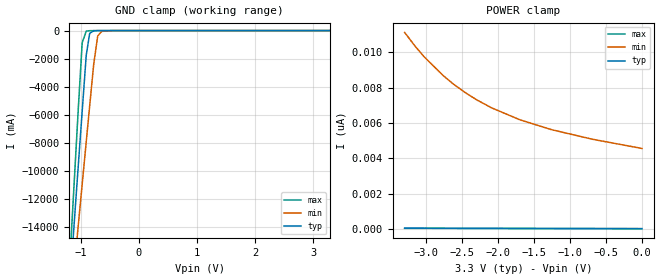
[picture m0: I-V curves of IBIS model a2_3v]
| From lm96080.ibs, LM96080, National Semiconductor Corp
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[Model] a2_3v
Model_type Input
Vinh = 2.0V
Vinl = 0.8V
C_comp   1.18pF   1.09pF   1.35pF
[Voltage Range]   3.3V   3.0V   3.6V
[Temperature Range]   25.0   125.0   -40.0
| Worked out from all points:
|   GND clamp passes 1 mA (typ) near -0.65 V on its own axis
[GND Clamp]
-3.3V     -140.9A    -112.5A    -173A
-1.171V   -17.28A    -19.67A    -15.31A
-1.102V   -13.23A    -16.62A    -10.16A
-1.043V   -9.774A    -14.01A    -5.763A
-973.5mV  -5.764A    -10.98A    -872.2mA
-904.2mV  -1.783A    -7.965A    -42.01mA
-844.8mV  -197.3mA   -5.398A    -8.068mA
-775.5mV  -19.36mA   -2.42A     -2.167mA
-706.2mV  -3.206mA   -385.4mA   -450.9uA
-636.9mV  -646.1uA   -55.93mA   -65.71uA
-438.9mV  -3.11uA    -355uA     -57.03nA
3.293V    21.88pA    0A         19.76pA
[POWER Clamp]
-3.3V     49.64pA    11.13nA    41.58pA
-3.161V   47.87pA    10.38nA    40.75pA
-3.033V   46.33pA    9.768nA    39.98pA
-2.765V   43.37pA    8.687nA    38.37pA
-2.627V   41.96pA    8.219nA    37.54pA
-2.458V   40.33pA    7.722nA    36.53pA
-2.3V     38.88pA    7.316nA    35.58pA
-2.092V   37.07pA    6.86nA     34.33pA
-1.696V   33.87pA    6.18nA     31.96pA
-1.261V   30.62pA    5.627nA    29.34pA
-696.3mV  26.64pA    5.087nA    25.96pA
-3.3mV    21.95pA    4.562nA    21.8pA
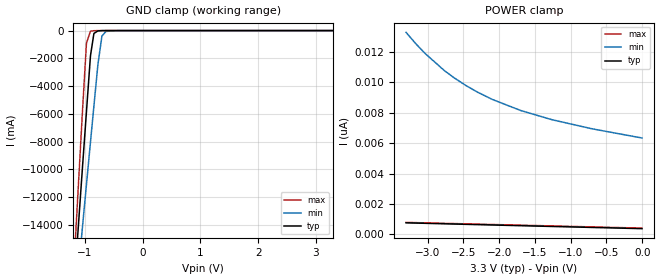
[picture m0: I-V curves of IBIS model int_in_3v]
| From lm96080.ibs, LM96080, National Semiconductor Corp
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[Model] int_in_3v
Model_type Input
Vinh = 2.0V
Vinl = 0.8V
C_comp   1.15pF   1.07pF   1.33pF
[Voltage Range]   3.3V   3.0V   3.6V
[Temperature Range]   25.0   125.0   -40.0
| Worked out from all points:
|   GND clamp passes 1 mA (typ) near -0.64 V on its own axis
[GND Clamp]
-3.3V     -142.3A    -113.8A    -174.6A
-1.171V   -17.47A    -19.9A     -15.46A
-1.102V   -13.36A    -16.8A     -10.25A
-1.043V   -9.856A    -14.14A    -5.81A
-973.5mV  -5.807A    -11.07A    -890.6mA
-904.2mV  -1.803A    -8.02A     -47.69mA
-844.8mV  -206.9mA   -5.432A    -9.694mA
-775.5mV  -22.71mA   -2.439A    -2.496mA
-706.2mV  -4.017mA   -395.4mA   -504uA
-636.9mV  -790.8uA   -60.84mA   -72.22uA
-438.9mV  -3.429uA   -514.1uA   -60.75nA
3.293V    377.6pA    0A         375.5pA
[POWER Clamp]
-3.3V     762.5pA    13.28nA    790pA
-3.161V   745.7pA    12.52nA    774.2pA
-3.033V   730.3pA    11.89nA    759.6pA
-2.765V   698.5pA    10.77nA    729.1pA
-2.627V   682.1pA    10.29nA    713.3pA
-2.458V   662.3pA    9.772nA    694.1pA
-2.3V     643.7pA    9.348nA    676pA
-2.092V   619.5pA    8.868nA    652.3pA
-1.696V   573.5pA    8.143nA    607.2pA
-1.261V   523.2pA    7.541nA    557.5pA
-696.3mV  458.3pA    6.939nA    493.2pA
-3.3mV    378.7pA    6.339nA    414.2pA
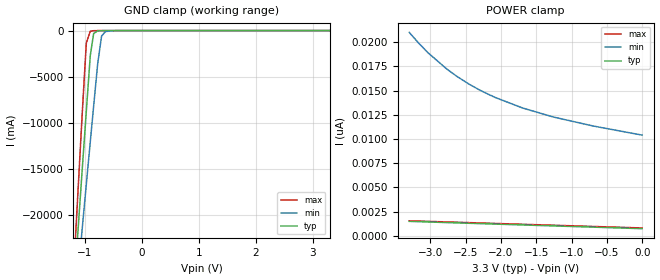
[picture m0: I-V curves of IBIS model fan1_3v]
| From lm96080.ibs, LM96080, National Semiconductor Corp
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[Model] fan1_3v
Model_type Input
Vinh = 2.1V
Vinl = 0.99V
C_comp   3.02pF   2.81pF   3.44pF
[Voltage Range]   3.3V   3.0V   3.6V
[Temperature Range]   25.0   125.0   -40.0
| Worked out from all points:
|   GND clamp passes 1 mA (typ) near -0.62 V on its own axis
[GND Clamp]
-3.3V     -214.3A    -171.4A    -262.7A
-1.171V   -26.3A     -29.96A    -23.27A
-1.102V   -20.1A     -25.28A    -15.41A
-1.043V   -14.82A    -21.28A    -8.74A
-973.5mV  -8.732A    -16.64A    -1.345A
-904.2mV  -2.715A    -12.06A    -74.37mA
-844.8mV  -315.1mA   -8.165A    -15.35mA
-775.5mV  -35.73mA   -3.667A    -3.909mA
-706.2mV  -6.43mA    -598.1mA   -782.7uA
-636.9mV  -1.259mA   -93.72mA   -111.6uA
-438.9mV  -5.304uA   -850.7uA   -92.98nA
3.293V    744.2pA    0A         741pA
[POWER Clamp]
-3.3V     1.5nA      21nA       1.559nA
-3.161V   1.468nA    19.85nA    1.528nA
-3.033V   1.437nA    18.89nA    1.499nA
-2.765V   1.375nA    17.2nA     1.439nA
-2.627V   1.343nA    16.47nA    1.408nA
-2.458V   1.304nA    15.68nA    1.37nA
-2.3V     1.268nA    15.04nA    1.334nA
-2.092V   1.22nA     14.31nA    1.287nA
-1.696V   1.13nA     13.2nA     1.198nA
-1.261V   1.031nA    12.27nA    1.1nA
-696.3mV  903.2pA    11.34nA    973.4pA
-3.3mV    746.5pA    10.4nA     817.5pA
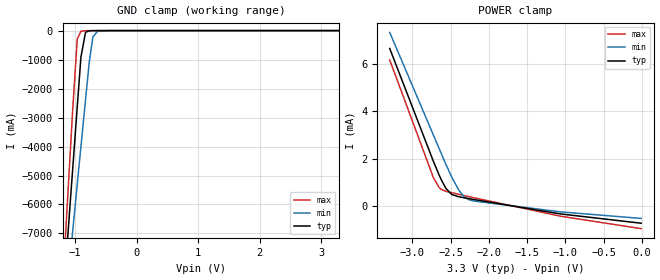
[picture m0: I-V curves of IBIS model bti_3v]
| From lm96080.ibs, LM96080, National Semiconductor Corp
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[Model] bti_3v
Model_type Input
Vinh = 2.0V
Vinl = 0.8V
C_comp   2.30pF   2.10pF   2.51pF
[Voltage Range]   3.3V   3.0V   3.6V
[Temperature Range]   25.0   125.0   -40.0
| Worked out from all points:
|   POWER clamp passes 1 mA (typ) near -2.60 V on its own axis
[GND Clamp]
-3.29V    -70.15A    -56.02A    -86.12A
-1.175V   -8.746A    -9.914A    -7.788A
-1.1V     -6.553A    -8.263A    -4.998A
-1.04V    -4.807A    -6.945A    -2.78A
-965mV    -2.638A    -5.305A    -292.7mA
-905mV    -915.6mA   -4.001A    -23.11mA
-830mV    -59.08mA   -2.381A    -4.486mA
-770mV    -9.278mA   -1.093A    -2.438mA
-710mV    -2.795mA   -215.3mA   -1.715mA
-635mV    -1.35mA    -27.25mA   -1.496mA
-440mV    -1.04mA    -881.8uA   -1.461mA
3.295V    -716.6uA   0A         -1.12mA
[POWER Clamp]
-3.295V   6.637mA    7.314mA    6.158mA
-2.725V   1.896mA    3mA        1.209mA
-2.65V    1.318mA    2.433mA    792.4uA
-2.62V    1.107mA    2.206mA    707.9uA
-2.56V    750.1uA    1.756mA    630.8uA
-2.485V   497uA      1.229mA    572.6uA
-2.395V   402.9uA    691.8uA    506.4uA
-2.32V    356.5uA    393.2uA    451.3uA
-2.26V    321.1uA    275.8uA    407.2uA
-2.2V     285.9uA    222.1uA    363.1uA
-1.06V    -322.7uA   -235.4uA   -418.8uA
-10mV     -712.3uA   -510.2uA   -940.6uA
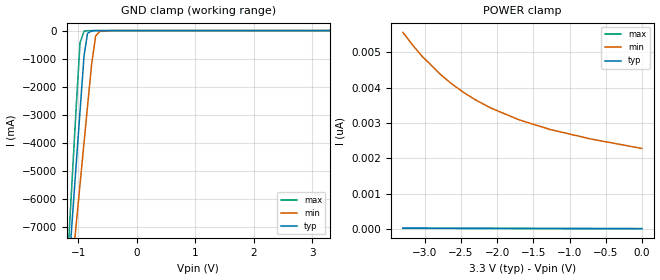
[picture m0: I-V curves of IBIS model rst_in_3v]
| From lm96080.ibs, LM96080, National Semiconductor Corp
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[Model] rst_in_3v
Model_type Input
Vinh = 2.0V
Vinl = 0.8V
C_comp   0.66pF   0.63pF   0.74pF
[Voltage Range]   3.3V   3.0V   3.6V
[Temperature Range]   25.0   125.0   -40.0
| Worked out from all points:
|   GND clamp passes 1 mA (typ) near -0.67 V on its own axis
[GND Clamp]
-3.3V     -70.44A    -56.24A    -86.49A
-1.171V   -8.642A    -9.836A    -7.656A
-1.102V   -6.616A    -8.311A    -5.079A
-1.043V   -4.887A    -7.006A    -2.881A
-973.5mV  -2.882A    -5.489A    -436.1mA
-904.2mV  -891.7mA   -3.983A    -21.01mA
-844.8mV  -98.65mA   -2.699A    -4.034mA
-775.5mV  -9.682mA   -1.21A     -1.083mA
-706.2mV  -1.603mA   -192.7mA   -225.4uA
-636.9mV  -323.1uA   -27.96mA   -32.85uA
-438.9mV  -1.555uA   -177.5uA   -28.52nA
3.293V    10.94pA    0A         9.88pA
[POWER Clamp]
-3.3V     24.82pA    5.565nA    20.79pA
-3.161V   23.94pA    5.192nA    20.38pA
-3.033V   23.16pA    4.884nA    19.99pA
-2.765V   21.69pA    4.344nA    19.19pA
-2.627V   20.98pA    4.11nA     18.77pA
-2.458V   20.17pA    3.861nA    18.27pA
-2.3V     19.44pA    3.658nA    17.79pA
-2.092V   18.54pA    3.43nA     17.17pA
-1.696V   16.94pA    3.09nA     15.98pA
-1.261V   15.31pA    2.813nA    14.67pA
-696.3mV  13.32pA    2.544nA    12.98pA
-3.3mV    10.97pA    2.281nA    10.9pA
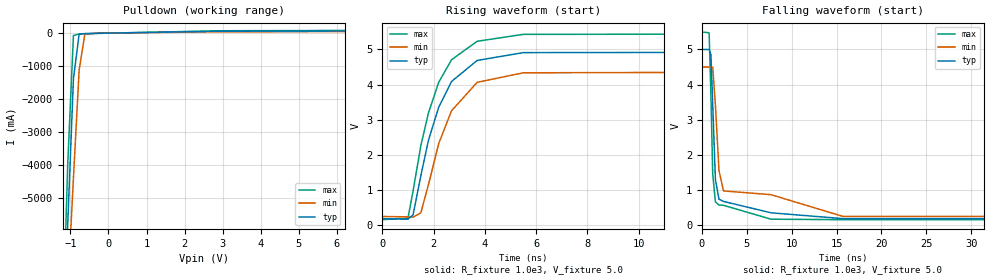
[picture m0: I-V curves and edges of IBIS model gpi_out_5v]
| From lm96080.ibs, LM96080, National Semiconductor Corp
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[Model] gpi_out_5v
Model_type Open_sink
Vmeas = 0.4V
Cref = 0.0pF
Rref = 1.0e3
Vref = 5.0V
C_comp   1.16pF   1.07pF   1.33pF
[Voltage Range]   5.0V   4.5V   5.5V
[Temperature Range]   25.0   125.0   -40.0
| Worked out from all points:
|   slope of the pulldown table from 0 to 0.75 V, typ, clamps not added: 38.1 ohm
|   rising waveform, R_fixture 1.0e3, V_fixture 5.0: 20-80 % time 1.22ns typ, 1.25ns min, 1.19ns max; typ from 0.17 V to 5 V
|   falling waveform, R_fixture 1.0e3, V_fixture 5.0: 20-80 % time 425ps typ, 736ps min, 312ps max; typ from 5 V to 0.17 V
[Pulldown]
-5V       -121.7A    -95.03A    -151.5A
-1.22V    -10.3A     -11.17A    -9.688A
-1.07V    -5.792A    -7.757A    -3.976A
-920mV    -1.386A    -4.392A    -75.54mA
-770mV    -30.71mA   -1.118A    -28.64mA
-620mV    -17.35mA   -31.1mA    -22.65mA
-305mV    -8.646mA   -5.705mA   -11.55mA
2.875V    53.3mA     36.61mA    67.81mA
10V       68.75mA    48.56mA    87.6mA
[Rising Waveform]
R_fixture=1.0e3
V_fixture=5.0
V_fixture_min=4.5
V_fixture_max=5.5
0s        170.3mV    231.6mV    140.1mV
1ns       153.4mV    220.5mV    188.2mV
1.2ns     279.8mV    212.2mV    962mV
1.5ns     1.39V      334mV      2.248V
1.8ns     2.41V      1.144V     3.19V
2.2ns     3.352V     2.314V     4.064V
2.7ns     4.086V     3.25V      4.707V
3.7ns     4.687V     4.062V     5.234V
5.5ns     4.91V      4.334V     5.432V
99.95ns   5V         4.5V       5.5V
[Falling Waveform]
R_fixture=1.0e3
V_fixture=5.0
V_fixture_min=4.5
V_fixture_max=5.5
0s        5V         4.5V       5.5V
800ps     5V         4.5V       5.475V
1ns       4.857V     4.5V       3.713V
1.2ns     3.431V     4.494V     1.451V
1.5ns     1.286V     3.414V     649.8mV
1.9ns     723.9mV    1.541V     557.7mV
2.4ns     661.6mV    961.3mV    551mV
7.7ns     336.5mV    854mV      153.9mV
15.7ns    170.4mV    234.2mV    140.2mV
99.95ns   170.3mV    231.6mV    140.1mV
[Ramp]
R_load = 1.0e3
dV/dt_r   2.897827E0/1.2E-9   2.561003E0/1.3E-9   3.215929E0/1.2E-9
dV/dt_f   2.89783E0/4E-10   2.561008E0/7E-10   3.215933E0/3E-10
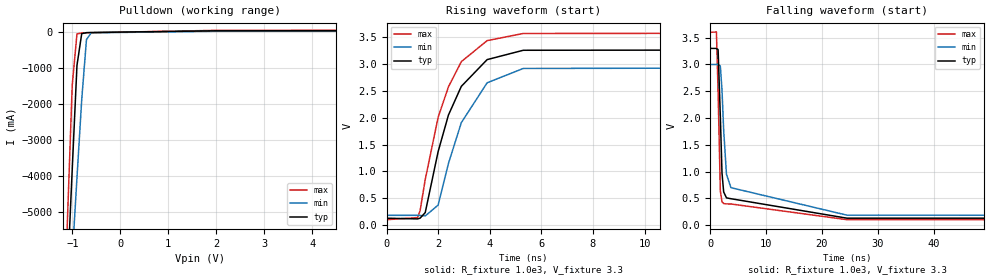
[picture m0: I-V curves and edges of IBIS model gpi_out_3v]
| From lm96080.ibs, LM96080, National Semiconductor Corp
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[Model] gpi_out_3v
Model_type Open_sink
Vmeas = 0.4V
Cref = 0.0pF
Rref = 1.0e3
Vref = 5.0V
C_comp   1.16pF   1.07pF   1.33pF
[Voltage Range]   3.3V   3.0V   3.6V
[Temperature Range]   25.0   125.0   -40.0
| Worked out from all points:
|   slope of the pulldown table from 0 to 0.495 V, typ, clamps not added: 43.7 ohm
|   rising waveform, R_fixture 1.0e3, V_fixture 3.3: 20-80 % time 1.26ns typ, 1.3ns min, 1.22ns max; typ from 0.129 V to 3.3 V
|   falling waveform, R_fixture 1.0e3, V_fixture 3.3: 20-80 % time 585ps typ, 1.22ns min, 393ps max; typ from 3.3 V to 0.129 V
[Pulldown]
-3.3V     -71.91A    -57.56A    -88.1A
-1.201V   -9.732A    -10.74A    -8.963A
-1.102V   -6.751A    -8.487A    -5.188A
-1.003V   -3.809A    -6.247A    -1.477A
-904.2mV  -926.6mA   -4.041A    -53.12mA
-805.2mV  -46.96mA   -1.877A    -28.28mA
-706.2mV  -19.05mA   -209.7mA   -23.38mA
-607.2mV  -14.94mA   -23.83mA   -20.14mA
1.996V    31.68mA    20.03mA    44.46mA
6.6V      35.4mA     22.46mA    49.81mA
[Rising Waveform]
R_fixture=1.0e3
V_fixture=3.3
V_fixture_min=3.0
V_fixture_max=3.6
0s        129.5mV    183.6mV    101.8mV
1.2ns     116.6mV    182.2mV    139.7mV
1.3ns     129.8mV    180.2mV    265.7mV
1.5ns     233.3mV    171.5mV    850mV
2ns       1.37V      373.9mV    2.009V
2.4ns     2.052V     1.15V      2.578V
2.9ns     2.587V     1.911V     3.047V
3.9ns     3.085V     2.653V     3.439V
5.3ns     3.259V     2.92V      3.572V
99.95ns   3.3V       3V         3.6V
[Falling Waveform]
R_fixture=1.0e3
V_fixture=3.3
V_fixture_min=3.0
V_fixture_max=3.6
0s        3.3V       3V         3.6V
1.1ns     3.3V       3V         3.607V
1.4ns     3.278V     3V         2.489V
1.8ns     2.034V     2.972V     638.8mV
2.1ns     975.9mV    2.523V     434.4mV
2.4ns     619mV      1.775V     403.9mV
2.9ns     509.5mV    951.5mV    396.3mV
3.7ns     493.4mV    699.6mV    395.1mV
24.5ns    129.6mV    186.1mV    101.8mV
99.95ns   129.5mV    183.6mV    101.8mV
[Ramp]
R_load = 1.0e3
dV/dt_r   1.902308E0/1.2E-9   1.689858E0/1.3E-9   2.098945E0/1.3E-9
dV/dt_f   1.90231E0/6E-10   1.689861E0/1.2E-9   2.098945E0/4E-10
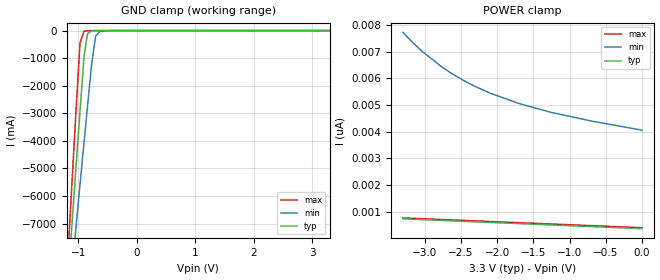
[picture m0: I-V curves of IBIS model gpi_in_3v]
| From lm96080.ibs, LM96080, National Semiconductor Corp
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[Model] gpi_in_3v
Model_type Input
Vinh = 2.0V
Vinl = 0.8V
C_comp   1.16pF   1.07pF   1.33pF
[Voltage Range]   3.3V   3.0V   3.6V
[Temperature Range]   25.0   125.0   -40.0
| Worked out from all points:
|   GND clamp passes 1 mA (typ) near -0.66 V on its own axis
[GND Clamp]
-3.3V     -71.91A    -57.56A    -88.1A
-1.171V   -8.827A    -10.06A    -7.809A
-1.102V   -6.741A    -8.485A    -5.168A
-1.043V   -4.968A    -7.137A    -2.929A
-973.5mV  -2.925A    -5.578A    -454.5mA
-904.2mV  -911.7mA   -4.037A    -26.68mA
-844.8mV  -108.2mA   -2.733A    -5.66mA
-775.5mV  -13.03mA   -1.229A    -1.413mA
-706.2mV  -2.413mA   -202.7mA   -278.6uA
-636.9mV  -467.8uA   -32.88mA   -39.36uA
-438.9mV  -1.874uA   -336.6uA   -32.23nA
3.293V    366.7pA    0A         365.6pA
[POWER Clamp]
-3.3V     737.7pA    7.718nA    769.2pA
-3.161V   721.8pA    7.327nA    753.9pA
-3.033V   707.1pA    7.003nA    739.6pA
-2.765V   676.8pA    6.43nA     709.9pA
-2.627V   661.1pA    6.18nA     694.5pA
-2.458V   642.1pA    5.911nA    675.8pA
-2.3V     624.3pA    5.69nA     658.2pA
-2.092V   600.9pA    5.438nA    635.2pA
-1.696V   556.6pA    5.053nA    591.2pA
-1.261V   507.9pA    4.728nA    542.9pA
-696.3mV  444.9pA    4.396nA    480.2pA
-3.3mV    367.8pA    4.058nA    403.3pA
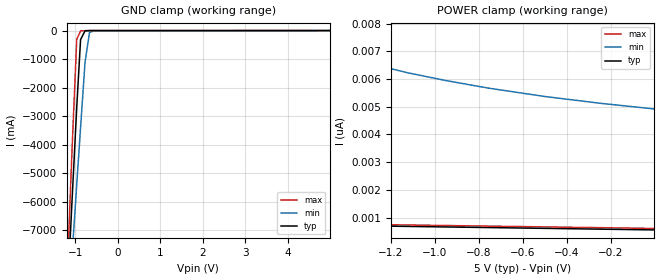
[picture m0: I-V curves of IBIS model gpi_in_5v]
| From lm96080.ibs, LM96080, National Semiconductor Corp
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[Model] gpi_in_5v
Model_type Input
Vinh = 2.0V
Vinl = 0.8V
C_comp   1.16pF   1.07pF   1.33pF
[Voltage Range]   5.0V   4.5V   5.5V
[Temperature Range]   25.0   125.0   -40.0
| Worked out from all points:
|   GND clamp passes 1 mA (typ) near -0.67 V on its own axis
[GND Clamp]
-5V       -121.7A    -95.03A    -151.5A
-1.175V   -8.933A    -10.14A    -7.943A
-1.07V    -5.778A    -7.753A    -3.951A
-965mV    -2.677A    -5.388A    -307.4mA
-875mV    -314.8mA   -3.394A    -11.37mA
-770mV    -11.26mA   -1.11A     -1.258mA
-665mV    -924.1uA   -67.37mA   -90.17uA
-560mV    -62.77uA   -5.338mA   -3.154uA
4.99V     555.9pA    0A         553.9pA
[POWER Clamp]
-5V       1.171nA    45.35nA    1.166nA
-1.82V    762.9pA    7.87nA     812.5pA
-1.76V    756pA      7.688nA    805.9pA
-1.565V   733.6pA    7.156nA    784.2pA
-1.46V    721.6pA    6.903nA    772.6pA
-1.31V    704.5pA    6.578nA    755.9pA
-1.115V   682.4pA    6.211nA    734.3pA
-950mV    663.7pA    5.944nA    716pA
-755mV    641.7pA    5.67nA     694.3pA
-500mV    613pA      5.37nA     666pA
-245mV    584.4pA    5.122nA    637.7pA
-5mV      557.5pA    4.923nA    611.1pA
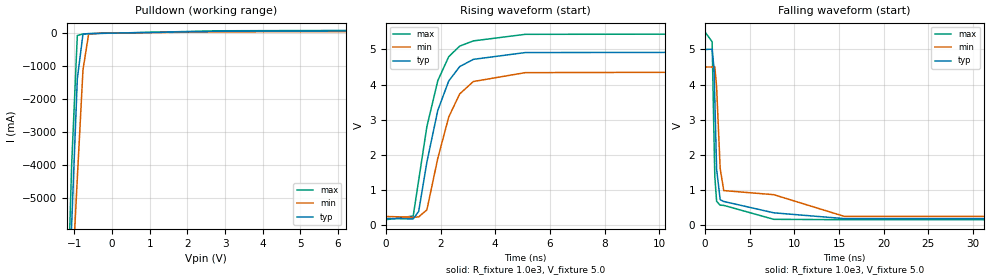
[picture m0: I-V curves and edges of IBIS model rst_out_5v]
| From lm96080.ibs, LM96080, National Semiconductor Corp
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[Model] rst_out_5v
Model_type Open_sink
Vmeas = 0.4V
Cref = 0.0pF
Rref = 1.0e3
Vref = 5.0V
C_comp   0.98pF   0.89pF   1.16pF
[Voltage Range]   5.0V   4.5V   5.5V
[Temperature Range]   25.0   125.0   -40.0
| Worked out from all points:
|   slope of the pulldown table from 0 to 0.75 V, typ, clamps not added: 38.1 ohm
|   rising waveform, R_fixture 1.0e3, V_fixture 5.0: 20-80 % time 892ps typ, 936ps min, 862ps max; typ from 0.17 V to 5 V
|   falling waveform, R_fixture 1.0e3, V_fixture 5.0: 20-80 % time 345ps typ, 606ps min, 258ps max; typ from 5 V to 0.17 V
[Pulldown]
-5V       -121.7A    -95.03A    -151.5A
-1.22V    -10.3A     -11.17A    -9.688A
-1.07V    -5.792A    -7.757A    -3.976A
-920mV    -1.386A    -4.392A    -75.54mA
-770mV    -30.71mA   -1.118A    -28.64mA
-620mV    -17.35mA   -31.1mA    -22.65mA
-305mV    -8.646mA   -5.705mA   -11.55mA
2.875V    53.3mA     36.61mA    67.81mA
10V       68.75mA    48.56mA    87.6mA
[Rising Waveform]
R_fixture=1.0e3
V_fixture=5.0
V_fixture_min=4.5
V_fixture_max=5.5
0s        170.3mV    231.6mV    140.1mV
1ns       162.3mV    211.1mV    245mV
1.2ns     378mV      219.9mV    1.268V
1.5ns     1.785V     420.9mV    2.798V
1.9ns     3.264V     1.894V     4.111V
2.3ns     4.101V     3.073V     4.795V
2.7ns     4.511V     3.73V      5.096V
3.2ns     4.718V     4.085V     5.245V
5.1ns     4.912V     4.339V     5.433V
99.95ns   5V         4.5V       5.5V
[Falling Waveform]
R_fixture=1.0e3
V_fixture=5.0
V_fixture_min=4.5
V_fixture_max=5.5
0s        5V         4.5V       5.5V
800ps     5.009V     4.5V       5.219V
1ns       4.484V     4.508V     2.572V
1.1ns     3.577V     4.509V     1.37V
1.3ns     1.583V     3.929V     665mV
1.7ns     712.1mV    1.601V     553.9mV
2.1ns     660.1mV    971.4mV    548.9mV
7.7ns     336.3mV    854mV      150.2mV
15.6ns    170.3mV    233.9mV    140.1mV
99.95ns   170.3mV    231.6mV    140.1mV
[Ramp]
R_load = 1.0e3
dV/dt_r   2.897827E0/9E-10   2.561003E0/1E-9   3.215929E0/9E-10
dV/dt_f   2.897832E0/3E-10   2.561008E0/6E-10   3.215933E0/3E-10
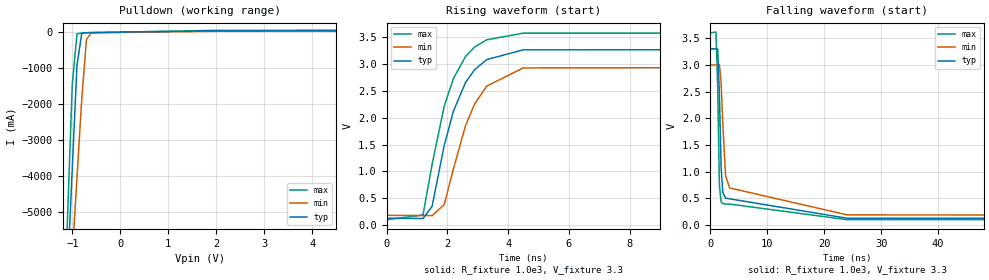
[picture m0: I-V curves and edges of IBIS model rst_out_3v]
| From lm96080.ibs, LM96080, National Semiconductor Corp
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[Model] rst_out_3v
Model_type Open_sink
Vmeas = 0.4V
Cref = 0.0pF
Rref = 1.0e3
Vref = 3.3V
C_comp   0.98pF   0.89pF   1.16pF
[Voltage Range]   3.3V   3.0V   3.6V
[Temperature Range]   25.0   125.0   -40.0
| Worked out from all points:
|   slope of the pulldown table from 0 to 0.495 V, typ, clamps not added: 43.7 ohm
|   rising waveform, R_fixture 1.0e3, V_fixture 3.3: 20-80 % time 964ps typ, 1.01ns min, 933ps max; typ from 0.129 V to 3.3 V
|   falling waveform, R_fixture 1.0e3, V_fixture 3.3: 20-80 % time 504ps typ, 1.06ns min, 339ps max; typ from 3.3 V to 0.129 V
[Pulldown]
-3.3V     -71.91A    -57.56A    -88.1A
-1.201V   -9.732A    -10.74A    -8.963A
-1.102V   -6.751A    -8.487A    -5.188A
-1.003V   -3.809A    -6.247A    -1.477A
-904.2mV  -926.6mA   -4.041A    -53.12mA
-805.2mV  -46.96mA   -1.877A    -28.28mA
-706.2mV  -19.05mA   -209.7mA   -23.38mA
-607.2mV  -14.94mA   -23.83mA   -20.14mA
1.996V    31.68mA    20.03mA    44.46mA
6.6V      35.4mA     22.46mA    49.81mA
[Rising Waveform]
R_fixture=1.0e3
V_fixture=3.3
V_fixture_min=3.0
V_fixture_max=3.6
0s        129.5mV    183.6mV    101.8mV
1.2ns     124.1mV    180.1mV    188.5mV
1.5ns     349.8mV    176.4mV    1.134V
1.9ns     1.486V     384.7mV    2.219V
2.2ns     2.122V     1.045V     2.733V
2.6ns     2.658V     1.855V     3.143V
2.9ns     2.898V     2.258V     3.32V
3.3ns     3.086V     2.593V     3.454V
4.5ns     3.267V     2.93V      3.578V
99.95ns   3.3V       3V         3.6V
[Falling Waveform]
R_fixture=1.0e3
V_fixture=3.3
V_fixture_min=3.0
V_fixture_max=3.6
0s        3.3V       3V         3.6V
1ns       3.3V       3V         3.617V
1.3ns     3.296V     3V         2.59V
1.6ns     2.463V     3.011V     749.2mV
1.9ns     1.09V      2.672V     434.6mV
2.2ns     613.6mV    1.886V     402.6mV
2.7ns     505.7mV    915.5mV    395.1mV
3.4ns     492.5mV    696.4mV    394.2mV
24ns      129.5mV    192.2mV    101.8mV
99.95ns   129.5mV    183.6mV    101.8mV
[Ramp]
R_load = 1.0e3
dV/dt_r   1.902308E0/1E-9   1.689858E0/1E-9   2.098945E0/9E-10
dV/dt_f   1.902311E0/5E-10   1.689861E0/1E-9   2.098947E0/3E-10
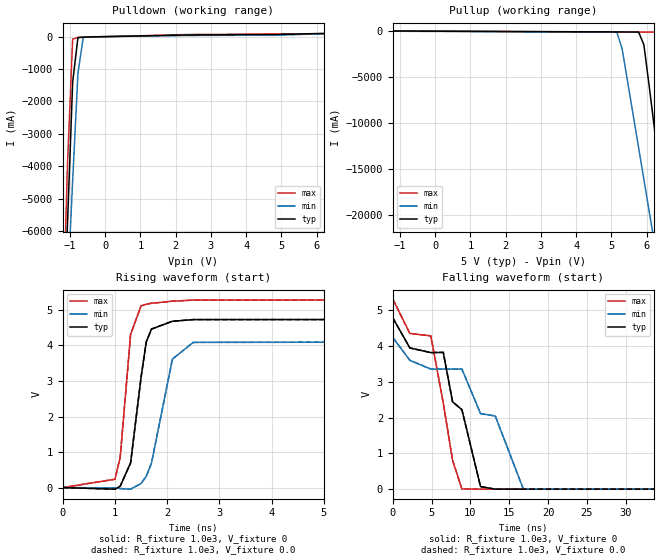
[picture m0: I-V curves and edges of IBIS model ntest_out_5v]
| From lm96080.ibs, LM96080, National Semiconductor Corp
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[Model] ntest_out_5v
Model_type Output
Vmeas = 1.4V
Cref = 0.0pF
Rref = 1.0e3
Vref = 0.0V
C_comp   2.30pF   2.02pF   2.64pF
[Voltage Range]   5.0V   4.5V   5.5V
[Temperature Range]   25.0   125.0   -40.0
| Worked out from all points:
|   slope of the pulldown table from 0 to 0.75 V, typ, clamps not added: 38.1 ohm
|   slope of the pullup table from 0 to 0.75 V, typ, clamps not added: 46.3 ohm
|   rising waveform, R_fixture 1.0e3, V_fixture 0: 20-80 % time 247ps typ, 334ps min, 184ps max; typ from 0 V to 4.78 V
|   falling waveform, R_fixture 1.0e3, V_fixture 0: 20-80 % time 7.37ns typ, 11.6ns min, 2.62ns max; typ from 4.78 V to 0 V
|   rising waveform, R_fixture 1.0e3, V_fixture 0.0: 20-80 % time 247ps typ, 334ps min, 184ps max; typ from 0 V to 4.78 V
|   falling waveform, R_fixture 1.0e3, V_fixture 0.0: 20-80 % time 7.37ns typ, 11.6ns min, 2.62ns max; typ from 4.78 V to 0 V
[Pullup]
-5V       99.31mA    81.34mA    113.2mA
5.155V    -66.49mA   -103.1mA   -80.99mA
5.305V    -67.01mA   -1.931A    -81.83mA
5.77V     -80.73mA   -12.62A    -83.58mA
5.92V     -1.452A    -16.11A    -83.86mA
6.07V     -5.93A     -19.57A    -84.11mA
6.37V     -15.2A     -26.46A    -95.62mA
6.52V     -19.8A     -29.89A    -2.187A
6.67V     -24.37A    -33.31A    -7.966A
6.97V     -33.47A    -40.12A    -19.71A
7.135V    -38.46A    -43.86A    -26.1A
10V       -123.9A    -108.1A    -135.1A
[Pulldown]
-5V       -123.9A    -96.97A    -153.9A
-1.22V    -10.52A    -11.42A    -9.881A
-1.07V    -5.883A    -7.899A    -4.033A
-920mV    -1.404A    -4.446A    -80.37mA
-770mV    -32.32mA   -1.13A     -28.73mA
-620mV    -17.4mA    -33.08mA   -22.65mA
-455mV    -12.74mA   -8.957mA   -16.95mA
2.26V     46.46mA    31.6mA     59.95mA
4.99V     65.71mA    44.61mA    81.06mA
6.355V    100.4mA    91.22mA    85.89mA
8.02V     155.3mA    121.7mA    168.8mA
10V       175.1mA    135.6mA    198.6mA
[Rising Waveform]
R_fixture=1.0e3
V_fixture=0
V_fixture_min=0
V_fixture_max=0
0s        2.008nV    68.39nV    1.655nV
1ns       -44.86mV   -10.16mV   233.9mV
1.1ns     38.52mV    -28.19mV   852.3mV
1.3ns     697.6mV    -44.25mV   4.316V
1.5ns     3.107V     114.8mV    5.115V
1.6ns     4.104V     317.2mV    5.162V
1.7ns     4.463V     690.5mV    5.188V
2.1ns     4.682V     3.616V     5.247V
2.5ns     4.729V     4.088V     5.278V
99.95ns   4.782V     4.234V     5.307V
[Falling Waveform]
R_fixture=1.0e3
V_fixture=0
V_fixture_min=0
V_fixture_max=0
0s        4.782V     4.234V     5.307V
2.2ns     3.942V     3.597V     4.347V
4.9ns     3.813V     3.353V     4.279V
6.5ns     3.818V     3.353V     2.406V
7.7ns     2.438V     3.353V     802.6mV
8.9ns     2.219V     3.352V     6.245mV
11.3ns    71.26mV    2.109V     57.57uV
13.2ns    78.65uV    2.042V     56.34uV
16.8ns    57.68uV    5.386mV    46.03uV
99.95ns   4.66uV     -20.52uV   8.689uV
[Rising Waveform]
R_fixture=1.0e3
V_fixture=0.0
V_fixture_min=0.0
V_fixture_max=0.0
0s        2.008nV    68.39nV    1.655nV
1ns       -44.86mV   -10.16mV   233.9mV
1.1ns     38.52mV    -28.19mV   852.3mV
1.3ns     697.6mV    -44.25mV   4.316V
1.5ns     3.107V     114.8mV    5.115V
1.6ns     4.104V     317.2mV    5.162V
1.7ns     4.463V     690.5mV    5.188V
2.1ns     4.682V     3.616V     5.247V
2.5ns     4.729V     4.088V     5.278V
99.95ns   4.782V     4.234V     5.307V
[Falling Waveform]
R_fixture=1.0e3
V_fixture=0.0
V_fixture_min=0.0
V_fixture_max=0.0
0s        4.782V     4.234V     5.307V
2.2ns     3.942V     3.597V     4.347V
4.9ns     3.813V     3.353V     4.279V
6.5ns     3.818V     3.353V     2.406V
7.7ns     2.438V     3.353V     802.6mV
8.9ns     2.219V     3.352V     6.245mV
11.3ns    71.26mV    2.109V     57.57uV
13.2ns    78.65uV    2.042V     56.34uV
16.8ns    57.68uV    5.386mV    46.03uV
99.95ns   4.66uV     -20.52uV   8.689uV
[Ramp]
R_load = 1.0e3
dV/dt_r   2.86923E0/2E-10   2.540292E0/3E-10   3.184285E0/1E-10
dV/dt_f   2.869226E0/7.3E-9   2.540303E0/1.17E-8   3.184278E0/2.6E-9
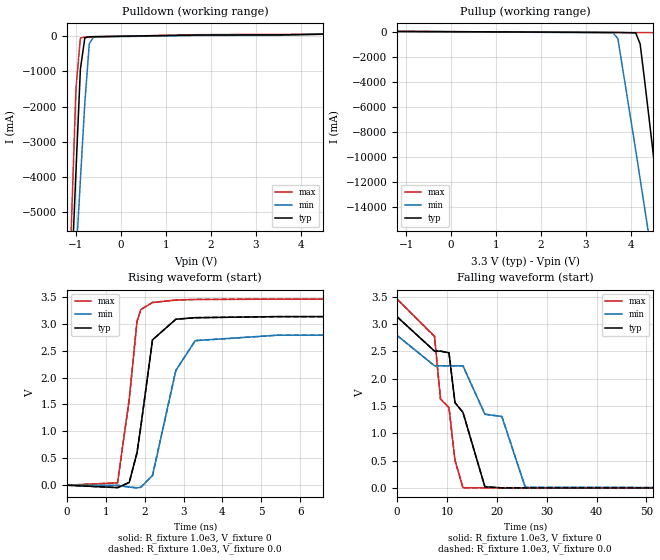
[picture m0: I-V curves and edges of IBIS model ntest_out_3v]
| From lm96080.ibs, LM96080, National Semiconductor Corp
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[Model] ntest_out_3v
Model_type Output
Vmeas = 1.4V
Cref = 0.0pF
Rref = 1.0e10
Vref = 0.0V
C_comp   2.30pF   2.02pF   2.64pF
[Voltage Range]   3.3V   3.0V   3.6V
[Temperature Range]   25.0   125.0   -40.0
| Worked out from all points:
|   slope of the pulldown table from 0 to 0.495 V, typ, clamps not added: 43.7 ohm
|   slope of the pullup table from 0 to 0.495 V, typ, clamps not added: 55 ohm
|   rising waveform, R_fixture 1.0e3, V_fixture 0: 20-80 % time 348ps typ, 477ps min, 278ps max; typ from 0 V to 3.13 V
|   falling waveform, R_fixture 1.0e3, V_fixture 0: 20-80 % time 5.01ns typ, 7.57ns min, 3.57ns max; typ from 3.13 V to 0 V
|   rising waveform, R_fixture 1.0e3, V_fixture 0.0: 20-80 % time 348ps typ, 477ps min, 278ps max; typ from 0 V to 3.13 V
|   falling waveform, R_fixture 1.0e3, V_fixture 0.0: 20-80 % time 5.01ns typ, 7.57ns min, 3.57ns max; typ from 3.13 V to 0 V
[Pullup]
-3.3V     87.68mA    70.17mA    101.7mA
3.6V      -31.43mA   -51.82mA   -43.09mA
3.709V    -31.53mA   -534.2mA   -43.25mA
4.105V    -64.23mA   -9.44A     -43.77mA
4.204V    -955.3mA   -11.76A    -43.89mA
4.303V    -3.873A    -14.07A    -44.1mA
4.402V    -6.879A    -16.37A    -45.47mA
4.501V    -9.945A    -18.66A    -55.63mA
4.6V      -13.01A    -20.94A    -444.6mA
4.709V    -16.36A    -23.44A    -4.395A
5.006V    -25.44A    -30.24A    -16.01A
6.6V      -73.38A    -66.3A     -77.17A
[Pulldown]
-3.3V     -73.38A    -58.87A    -89.7A
-1.201V   -9.934A    -10.98A    -9.137A
-1.102V   -6.867A    -8.653A    -5.27A
-1.003V   -3.859A    -6.344A    -1.5A
-904.2mV  -941.2mA   -4.088A    -56.56mA
-805.2mV  -50.01mA   -1.895A    -28.56mA
-706.2mV  -19.49mA   -215.6mA   -23.39mA
-607.2mV  -14.97mA   -25.48mA   -20.14mA
1.7V      29.42mA    18.67mA    41.04mA
3.491V    33.97mA    22.06mA    48.13mA
4.392V    53.63mA    54.06mA    48.56mA
6.6V      130.9mA    101mA      155.8mA
[Rising Waveform]
R_fixture=1.0e3
V_fixture=0
V_fixture_min=0
V_fixture_max=0
0s        1.523nV    79.33nV    1.201nV
1.3ns     -44.32mV   -2.68mV    44.7mV
1.6ns     51.3mV     -34.01mV   1.594V
1.8ns     602mV      -48.93mV   3.041V
1.9ns     1.096V     -37.82mV   3.264V
2.2ns     2.701V     181.6mV    3.395V
2.8ns     3.083V     2.132V     3.44V
3.3ns     3.112V     2.686V     3.451V
5.4ns     3.132V     2.786V     3.456V
99.95ns   3.133V     2.791V     3.457V
[Falling Waveform]
R_fixture=1.0e3
V_fixture=0
V_fixture_min=0
V_fixture_max=0
0s        3.133V     2.791V     3.457V
7.5ns     2.505V     2.236V     2.775V
8.7ns     2.504V     2.236V     1.626V
10.4ns    2.474V     2.236V     1.47V
11.6ns    1.562V     2.236V     506.2mV
13.2ns    1.382V     2.236V     2.747mV
17.6ns    19.29mV    1.349V     39.82uV
21ns      53.89uV    1.307V     33.46uV
25.7ns    35.93uV    8.857mV    26.64uV
99.95ns   -14.04uV   -18.25uV   3.023uV
[Rising Waveform]
R_fixture=1.0e3
V_fixture=0.0
V_fixture_min=0.0
V_fixture_max=0.0
0s        1.523nV    79.33nV    1.201nV
1.3ns     -44.32mV   -2.68mV    44.7mV
1.6ns     51.3mV     -34.01mV   1.594V
1.8ns     602mV      -48.93mV   3.041V
1.9ns     1.096V     -37.82mV   3.264V
2.2ns     2.701V     181.6mV    3.395V
2.8ns     3.083V     2.132V     3.44V
3.3ns     3.112V     2.686V     3.451V
5.4ns     3.132V     2.786V     3.456V
99.95ns   3.133V     2.791V     3.457V
[Falling Waveform]
R_fixture=1.0e3
V_fixture=0.0
V_fixture_min=0.0
V_fixture_max=0.0
0s        3.133V     2.791V     3.457V
7.5ns     2.505V     2.236V     2.775V
8.7ns     2.504V     2.236V     1.626V
10.4ns    2.474V     2.236V     1.47V
11.6ns    1.562V     2.236V     506.2mV
13.2ns    1.382V     2.236V     2.747mV
17.6ns    19.29mV    1.349V     39.82uV
21ns      53.89uV    1.307V     33.46uV
25.7ns    35.93uV    8.857mV    26.64uV
99.95ns   -14.04uV   -18.25uV   3.023uV
[Ramp]
R_load = 1.0e3
dV/dt_r   1.87955E0/3E-10   1.67483E0/5E-10   2.074007E0/3E-10
dV/dt_f   1.879557E0/5E-9   1.674839E0/7.6E-9   2.074004E0/3.5E-9
